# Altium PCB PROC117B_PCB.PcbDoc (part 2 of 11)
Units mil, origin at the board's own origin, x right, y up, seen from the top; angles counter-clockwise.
Board outline 2480.32 x 3185.25 mil, 8 copper layers (Top Layer, L2_GND1, L3_SIG1, L4_PWR1, L5_PWR2, L6_SIG2, L7_GND2, Bottom Layer), stack 57.4 mil thick; 456 components, 292 nets, 7831 pads, 2905 vias.

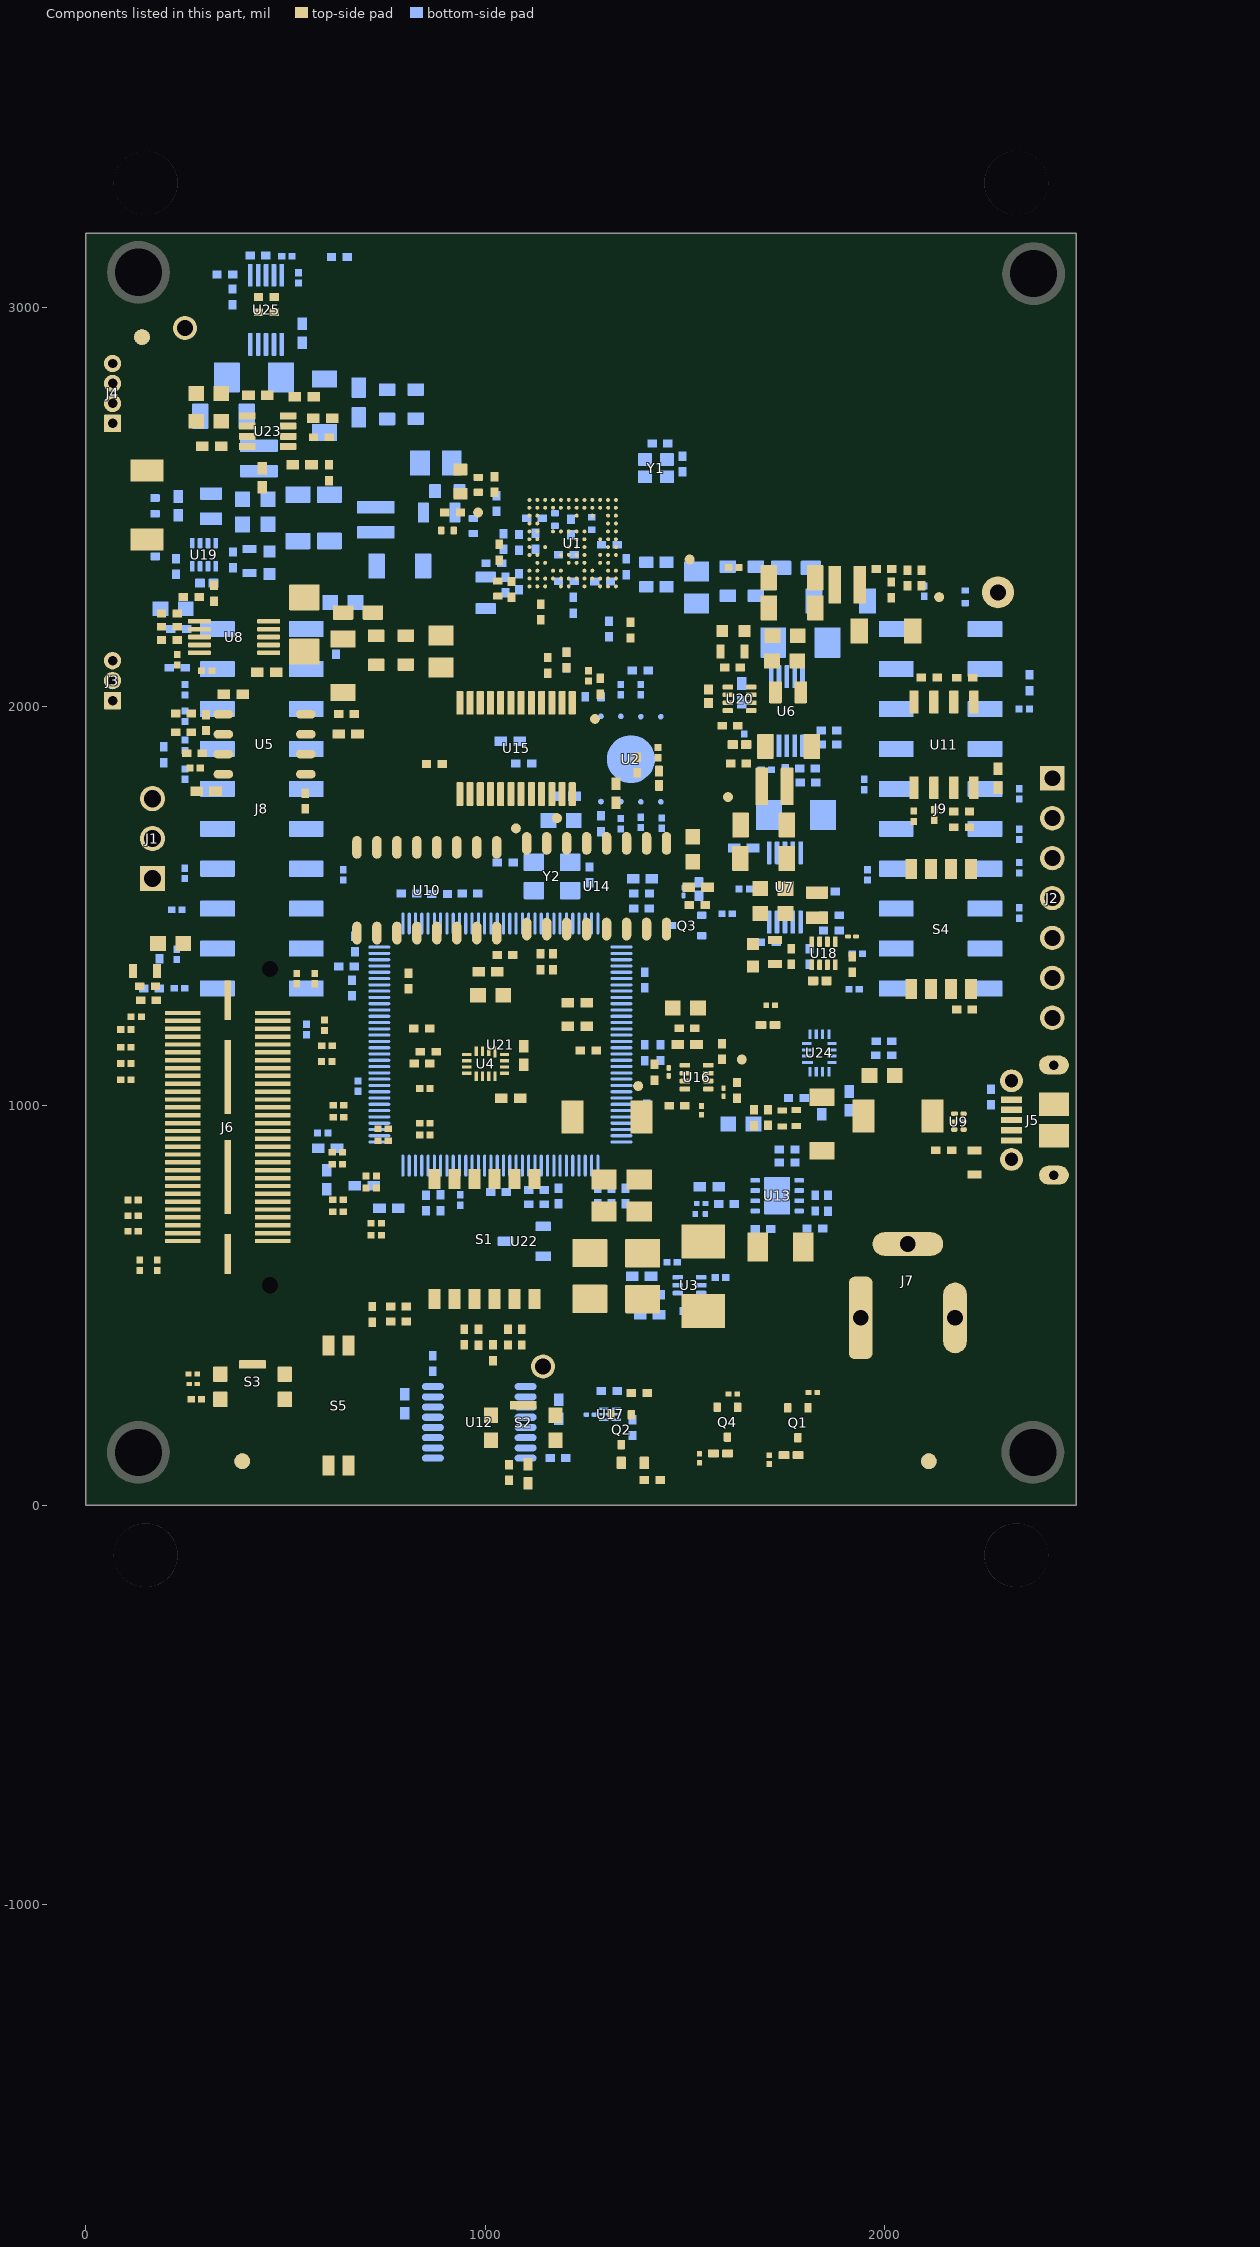
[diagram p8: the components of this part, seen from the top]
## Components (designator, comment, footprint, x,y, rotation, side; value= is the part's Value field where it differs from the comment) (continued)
R137 "CRCW02010000Z0ED" 0201 532.63,3073.14 r270 bottom
R138 "CRCW040210K0FKED" 0402L 1369.02,194.08 r270 bottom
R139 "CRCW02010000Z0ED" 0201 503.6,3127.45 r0 bottom
R140 "CRCW02010000Z0ED" 0201_Silk 2350.08,1993.71 r0 bottom
R141 "RC0201JR-07510RL" 0201L 1711.5,114.16 r90 top
R142 "CRCW040210K0FKED" 0402L 431.44,3128.96 r0 bottom
R143 "CRCW02010000Z0ED" 0201_Silk 1949.41,1804.6 r270 bottom
R144 "CRCW02010000Z0ED" 0201_Silk 2337.72,1781.04 r270 bottom
R145 "CRCW02010000Z0ED" 0201_Silk 2337.72,1679.83 r270 bottom
R146 "CRCW02010000Z0ED" 0201_Silk 247.61,1581.92 r90 bottom
R147 "CRCW02010000Z0ED" 0201_Silk 1957.66,1578.25 r90 bottom
R148 "CRCW040210K0FKED" 0402L 452.2,2987.41 r180 top
R149 "CRCW02010000Z0ED" 0201_Silk 228.01,1491.41 r0 bottom
R150 "CRCW040210K0FKED" 0402L 367.15,3025.77 r90 bottom
R151 "CRCW04020000Z0ED" 0402 1411.3,526.51 r0 bottom
R152 "CRCW040210K0FKED" 0402L 1998.2,1126.65 r0 bottom
R153 "CRCW02010000Z0ED" 0201_Silk 2337.72,1596.25 r90 bottom
R154 "CRCW02010000Z0ED" 0201_Silk 227.56,1379.15 r90 bottom
R155 "CRCW02010000Z0ED" 0201_Silk 1932.27,1380.28 r0 bottom
R156 "ERJ-2GE0R00X" 0402L 841.93,1105.72 r0 top
R157 "CRCW040210K0FKED" 0402L 2193.38,1737.31 r0 top
R158 "CRCW040210K0FKED" 0402L 2193.38,1697.45 r180 top
R159 "CRCW02010000Z0ED" 0201 2124.33,1728.34 r270 top
R160 "CRCW02010000Z0ED" 0201 2073.05,1724.99 r270 top
R161 "CRCW040210K0FKED" 0402L 2200.92,2071.84 r0 top
R162 "CRCW040210K0FKED" 0402L 2112.15,2072.49 r0 top
R163 "CRCW02010000Z0ED" 0201_Silk 234.77,1294.83 r0 bottom
R164 "CRCW02010000Z0ED" 0201_Silk 1924,1291.98 r0 bottom
R165 "CRCW040210K0FKED" 0402L 1059.52,81.96 r270 top
R169 "ERJ-2GEJ101X" 0402L 1391.89,1531.41 r0 bottom
R170 "ERJ-2GE0R00X" 0402 1394.09,1568.73 r0 bottom
R171 "RC0201JR-07510RL" 0201L 1821,281.86 r180 top
R172 "ERJ-2GEJ511X" 0402L 1418.73,62.98 r0 top
R173 "RC0201JR-070RL" "FP-RC0201JR-070RL_0201 (0603 Metric)-IPC_C" 1496.97,1536.63 r90 bottom
R174 "RC0201JR-07510RL" 0201L 1714.78,1251.78 r0 top
R175 "CRCW0402100KFKEDC" FP-CRCW0402100KFKEDC_0402-IPC_B 1637.01,1904.61 r0 top
R176 "RC0201JR-070RL" "FP-RC0201JR-070RL_0201 (0603 Metric)-IPC_C" 1918.75,1423.57 r180 top
R177 "CRCW0402100KFKEDC" FP-CRCW0402100KFKEDC_0402-IPC_B 1535.32,1542.64 r270 bottom
R178 "CRCW040218K0FKED" 0402L 225.59,2350.58 r270 bottom
R179 "ERJ-2GEJ511X" 0402L 1385.79,280.58 r180 top
R180 "CRCW040218K0FKED" 0402L 1613.02,1951.77 r180 top
R181 "ERJ-2GE0R00X" 0402 696.96,800.08 r180 bottom
R182 "HCJ0603ZT0R00" FP-HCJ0603ZT0R00_0603-MFG 1778.48,2346.91 r180 bottom
R183 "HCJ0603ZT0R00" FP-HCJ0603ZT0R00_0603-MFG 681.62,2235.22 r0 top
R188 "ERJ-2GE0R00X" 0402 605.47,893.62 r0 bottom
R190 "CRCW02010000Z0ED" 0201_Silk 937.61,763.99 r90 bottom
R191 "CRCW04021K00FKED" 0402L 674.18,1405.38 r90 bottom
R192 "WSL1206R0400FEB" FP-WSL1206R0400FEB_1206-MFG 1789.48,2159.94 r180 bottom
R193 "WSL1206R0400FEB" FP-WSL1206R0400FEB_1206-MFG 547.27,2205.5 r270 top
R194 "CRCW04021K00FKED" 0402L 652.72,1348.51 r180 bottom
R195 "CRCW04021K00FKED" 0402L 841.25,1193.16 r180 top
R196 "CRCW04021K00FKED" 0402L 808.39,1312.74 r270 top
R197 "ERJ-2GE0R00X" 0402 1230.59,1257.95 r0 top
R198 "RC0201JR-070RL" "FP-RC0201JR-070RL_0201 (0603 Metric)-MFG" 1538.99,728.87 r180 bottom
R199 "ERJ-2GE0R00X" 0402 1230.59,1198.69 r0 top
R200 "WSL1206R0400FEB" FP-WSL1206R0400FEB_1206-MFG 1778.3,1728.34 r0 bottom
R201 "CRCW0201100KFKED" 0201L 1540.68,755.51 r0 bottom
R202 "CRCW040249R9FKED" 0402L 962.23,1531.94 r180 bottom
R203 "CRCW040210K0FKED" 0402L 857.45,1135.38 r0 top
R204 "CRCW04027K87FKED" 0402L 783.2,497.74 r0 top
R205 "CRCW040282K5FKED" 0402L 717.37,477.73 r90 top
R206 "CRCW040210K0FKED" 0402L 1056.91,420.72 r270 top
R207 "CRCW04027K87FKED" 0402L 983.78,420.38 r90 top
R208 "CRCW040282K5FKED" 0402L 1019.54,381.59 r90 top
R213 "RC0201JR-07220RL" 0201 277,264.9 r180 top
R214 "RC0201JR-070RL" "FP-RC0201JR-070RL_0201 (0603 Metric)-IPC_C" 269.29,303.27 r180 top
R215 "CRCW0201100KFKED" 0201L 268.39,327.93 r180 top
R219 "CRCW02010000Z0ED" 0201_Silk 632.84,1001.22 r0 top
R220 "CRCW02010000Z0ED" 0201_Silk 632.84,971.22 r0 top
R221 "CRCW02010000Z0ED" 0201_Silk 744.45,942.84 r0 top
R222 "CRCW02010000Z0ED" 0201_Silk 744.45,912.84 r0 top
R223 "CRCW02010000Z0ED" 0201_Silk 630.17,884 r0 top
R224 "CRCW02010000Z0ED" 0201_Silk 630.17,854 r0 top
R225 "CRCW02010000Z0ED" 0201_Silk 714.97,824.08 r0 top
R226 "CRCW02010000Z0ED" 0201_Silk 714.97,794.08 r0 top
R227 "CRCW02010000Z0ED" 0201_Silk 631.62,765.03 r0 top
R228 "CRCW02010000Z0ED" 0201_Silk 631.62,735.03 r0 top
R229 "CRCW02010000Z0ED" 0201_Silk 727.5,705.97 r0 top
R230 "CRCW02010000Z0ED" 0201_Silk 727.5,675.97 r0 top
R231 "CRCW040210K0FKED" 0402L 886.06,1530.6 r180 bottom
R232 "CRCW0402100KFKEDC" FP-CRCW0402100KFKEDC_0402-IPC_B 1838.13,1313.11 r0 top
R233 "CRCW04021K00FKED" 0402L 1183.89,774.29 r90 bottom
R234 "CRCW04024K87FKED" 0402L 666.49,1294.83 r90 bottom
R236 "CRCW0402330KFKED" 0402L 1351.75,773.94 r270 bottom
R238 "CRCW0402100KFKEDC" FP-CRCW0402100KFKEDC_0402-IPC_B 302.89,2308.62 r180 bottom
R239 "CRCW0402330KFKED" 0402L 1282.09,773.94 r90 bottom
R241 "ERJ-2GE0R00X" 0402 1560.96,797.47 r0 bottom
R244 "CRCW0402100KFKEDC" FP-CRCW0402100KFKEDC_0402-IPC_B 1559.69,2025.63 r270 top
S1 "218-6LPST" SW_218-6LPST 998.28,666.28 r90 top
S2 "KMR243GLFG" SW_KMR243GLFG 1095.36,193.75 r0 top
S3 "KMR243GLFG" SW_KMR243GLFG 417.49,296.36 r0 top
S4 "218-4LPST" SW_218-4LPST 2142.14,1442.74 r270 top
S5 "218-2LPST" SW_218-2LP 632.84,249.25 r90 top
TP1 "TESTPOINT" TP_VIA_060RND040 1145.25,347.45 r270 top
TP2 "TESTPOINT" TP_25MIL-SMT 1274.9,1968.89 r90 top
TP3 "TESTPOINT" TP_25MIL-SMT 1077.13,1694.73 r90 top
TP4 "TESTPOINT" TP_25MIL-SMT 1180.04,1720.28 r90 top
TP5 "TESTPOINT" TP_25MIL-SMT 1512.19,2368.21 r90 top
TP6 "TESTPOINT" TP_25MIL-SMT 982.47,2485.72 r90 top
TP7 "TESTPOINT" TP_25MIL-SMT 2137.05,2273.88 r90 top
TP8 "TESTPOINT" TP_25MIL-SMT 1642.77,1116.02 r0 top
TP9 "TESTPOINT" TP_25MIL-SMT 1608.13,1773.05 r0 top
TP10 "5001" Keystone5001 2284.36,2285.93 r90 top
TP11 "TESTPOINT" TP_VIA_060RND040 248.36,2947.57 r180 top
TP12 "TESTPOINT" TP_25MIL-SMT 1383.24,1049.37 r180 top
U1 "IWRL6432QGAMF" AMF0102A-MFG 1219.26,2408.99 r270 top locked
U2 "MX25V1635FZNQ03" FP-MX25V1635FZNQ03_WSON8-MFG 1365.12,1868.19 r270 bottom
U3 "TMP112AQDRLRQ1" DRL0006A 1511.78,550.63 r180 bottom
U4 "TS3A5018RSVR" RSV0016A 1001.27,1105.02 r270 top
U5 "TCAN1042HGVDQ1" D0008A_L 447.73,1905.45 r0 top
U6 "INA228AIDGST" DGS0010A-MFG 1755.6,1988.23 r90 bottom
U7 "INA228AIDGST" DGS0010A-MFG 1750.8,1546.8 r90 bottom
U8 "INA228AIDGST" DGS0010A-MFG 371.18,2173.77 r0 top
U9 "TPD4E004DRYR" DRY0006A 2186.45,960.29 r0 top
U10 "SN65LVDS31MDREP" D0016A_N 854.03,1539.9 r270 top locked
U11 "CAT24C08WI-GT3" SOIC-8 2148.96,1903.96 r270 top
U12 "TS3A44159PWR" PW0016A_N 985.32,207.25 r0 bottom
U13 "TPS79601DRBR" DRB0008B 1731.38,774.87 r180 bottom
U14 "SN65LVDS31MDREP" D0016A_N 1279.22,1549.9 r270 top locked
U15 "TS3A27518EPWR" PW0024A-MFG 1077.43,1894.93 r270 top
U16 "TPS2116DRLR" DRL0008A-MFG 1529.63,1071.74 r0 top
U17 "SN74LVC1G11DSFR" DSF0006A 1312.89,227.49 r180 bottom
U18 "TPS6285021HQDRLRQ1" DRL0008A-MFG 1847.48,1382.07 r90 top
U19 "TPS628502QDRLRQ1" DRL0008A-MFG 296,2380.17 r90 bottom
U20 "TPS6285020MQDRLRQ1" DRL0008A-MFG 1637.3,2019.27 r0 top
U21 "TM4C1294NCPDTT3" PDT0128A 1038.21,1153.31 r90 bottom locked
U22 "LM4040C25QDBZR" DBZ0003A_N 1098.48,660.56 r180 bottom
U23 "TLIN1039DDFRQ1" DDF0008A-MFG 455.49,2689.41 r180 top
U24 "TS3A5018RSVR" RSV0016A 1837.22,1132.23 r0 bottom
U25 "INA228AIDGST" DGS0010A-MFG 451.49,2993.23 r270 bottom
Y1 "FW4000044Q" FP-FW4000044Q_4-SMD-2.0x1.6mm-MFG 1427.89,2596.78 r180 bottom
Y2 "ECS-160-8-33Q-RES-TR" FP-ECS-160-8-33Q-RES-TR_SMT4_3MM2_2MM5-MFG 1167.48,1574.31 r0 bottom
ZZ1 "This Assembly Note is for PCB labels only" AssemblyNoteLabel -715.46,4127.58 r0 top
ZZ2 "These assemblies are ESD sensitive, ESD precautions shall be observed." AssemblyNote -713.05,4049.6 r0 top
ZZ3 "These assemblies must be clean and free from flux and all contaminants. Use of no clean flux is not acceptable." AssemblyNote -713.05,3962.79 r0 top
ZZ4 "These assemblies must comply with workmanship standards IPC-A-610 Class 2, unless otherwise specified." AssemblyNote -692.48,3894.06 r0 top
ZZ5 "INDICATION FOR COMPONENTS D* ARE GIVEN AT THEIR CATHODE SIDE." AssemblyNote -691.09,3806.47 r0 top

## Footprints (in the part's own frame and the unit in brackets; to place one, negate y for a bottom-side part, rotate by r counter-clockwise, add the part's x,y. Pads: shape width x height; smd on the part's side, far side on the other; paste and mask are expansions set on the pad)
0201 [mm] "Data from Kemet datasheet CC101_COM dated 7/28/11"
  rect 0.46x0.42 smd mask+0: 1(-0.33,0) 2(0.33,0)
0201_Silk [mm] "Data from Kemet datasheet CC101_COM dated 7/28/11"
  rect 0.46x0.42 smd mask+0: 1(-0.33,0) 2(0.33,0)
  silkscreen extent -0.75,-0.4 0.75,0.4
0201L [mm] "Data from Kemet datasheet CC101_COM dated 7/28/11"
  rect 0.36x0.32 smd mask+0: 1(-0.28,0) 2(0.28,0)
0402 [mm] "0402 from SM-752 data"
  rect 0.8x0.6 smd: 1(-0.6,0) 2(0.6,0)
  silkscreen extent -1.22,-0.52 1.22,0.52
0402_065L [mm] "0402"
  rect 0.6x0.5 smd: 1(-0.5,0) 2(0.5,0)
0402_070 [mil] "SMD, 2-Leads, Body 1.2x0.7mm, Height 0.7mm"
  rect 15x24 smd: 1(-20,0) 2(20,0)
0402L [mm] "0402 from SM-752 data"
  rect 0.6x0.5 smd: 1(-0.5,0) 2(0.5,0)
0603 [mm] "0603 from SM-752 data"
  rect 1x0.95 smd: 1(-0.8,0) 2(0.8,0)
  silkscreen extent -1.52,-0.69 1.52,0.69
0603_HV [mil] "Ernesto recommended land pattern.  26 mil between pads."
  rect 30x30 smd: 1(-28,0) 2(28,0)
  silkscreen extent -52,-24 52,24
0603S [mil]
  rect 20x35 smd: 1(-30,0) 2(30,0)
0805_HV [mil] "0805 with 30mil clearance between pads"
  rect 50x63 smd: 1(-40,0) 2(40,0)
  silkscreen extent -74,-40 74,40
1206 [mm] "1206 from SM-752 data"
  rect 1.3x1.85 smd: 1(-1.45,0) 2(1.45,0)
  silkscreen extent -2.4,-1.21 2.4,1.21
1206_180 [mm] "1206_180"
  rect 1.1x1.6 smd: 1(-1.7,0) 2(1.7,0)
  silkscreen extent -0.9,-1 0.9,1
3528-21 [mm] "Medium Density IPC, based on Kemet datasheet 2016-10-20"
  rrect6% 1.8x2.23 smd: 1(-1.46,0) 2(1.46,0)
  silkscreen extent -2.29,-1.5 0.76,1.5
AMF0102A-MFG [mm]
  round 0.25 smd paste+0 mask+0: A1(-2.75,2.75) A2(-2.25,2.75) A3(-1.75,2.75) A4(-1.25,2.75) A5(-0.75,2.75) A6(-0.25,2.75) A7(0.25,2.75) A8(0.75,2.75) A10(1.75,2.75) A11(2.25,2.75) A12(2.75,2.75) B1(-2.75,2.25) B2(-2.25,2.25) B3(-1.75,2.25) B4(-1.25,2.25) B5(-0.75,2.25) B6(-0.25,2.25) B7(0.25,2.25) B8(0.75,2.25) B9(1.25,2.25) B10(1.75,2.25) B11(2.25,2.25) B12(2.75,2.25) C1(-2.75,1.75) C2(-2.25,1.75) C6(-0.25,1.75) C8(0.75,1.75) C9(1.25,1.75) C11(2.25,1.75) C12(2.75,1.75) D1(-2.75,1.25) D2(-2.25,1.25) D3(-1.75,1.25) D10(1.75,1.25) D11(2.25,1.25) E1(-2.75,0.75) E2(-2.25,0.75) E5(-0.75,0.75) E6(-0.25,0.75) E7(0.25,0.75) E8(0.75,0.75) E9(1.25,0.75) E10(1.75,0.75) E11(2.25,0.75) E12(2.75,0.75) F1(-2.75,0.25) F2(-2.25,0.25) F3(-1.75,0.25) F5(-0.75,0.25) F6(-0.25,0.25) F7(0.25,0.25) F8(0.75,0.25) F9(1.25,0.25) F11(2.25,0.25) G1(-2.75,-0.25) G2(-2.25,-0.25) G5(-0.75,-0.25) G7(0.25,-0.25) G8(0.75,-0.25) G9(1.25,-0.25) G11(2.25,-0.25) G12(2.75,-0.25) H1(-2.75,-0.75) H2(-2.25,-0.75) H5(-0.75,-0.75) H8(0.75,-0.75) H10(1.75,-0.75) H11(2.25,-0.75) H12(2.75,-0.75) J1(-2.75,-1.25) J2(-2.25,-1.25) J5(-0.75,-1.25) J10(1.75,-1.25) J11(2.25,-1.25) K1(-2.75,-1.75) K2(-2.25,-1.75) K7(0.25,-1.75) K9(1.25,-1.75) K11(2.25,-1.75) K12(2.75,-1.75) L1(-2.75,-2.25) L2(-2.25,-2.25) L3(-1.75,-2.25) L4(-1.25,-2.25) L5(-0.75,-2.25) L6(-0.25,-2.25) L8(0.75,-2.25) L9(1.25,-2.25) L10(1.75,-2.25) L11(2.25,-2.25) L12(2.75,-2.25) M1(-2.75,-2.75) M2(-2.25,-2.75) M3(-1.75,-2.75) M4(-1.25,-2.75) M5(-0.75,-2.75) M6(-0.25,-2.75) M7(0.25,-2.75) M8(0.75,-2.75) M10(1.75,-2.75) M11(2.25,-2.75) M12(2.75,-2.75)
  silkscreen extent -3.87,-3.27 3.27,3.27
APHHS1005_Green [mm] "SMD, 2-Leads, Body 1x0.5mm"
  rrect20% 0.7x0.5 smd: 1(-0.45,0) 2(0.45,0)
  silkscreen extent -0.8,-0.65 1.2,0.65
APHHS1005_Red [mm] "SMD, 2-Leads, Body 1x0.5mm"
  rrect20% 0.7x0.5 smd: 1(-0.45,0) 2(0.45,0)
  silkscreen extent -0.8,-0.65 1.2,0.65
AssemblyNote [mil] "Assembly Note"
AssemblyNoteLabel [mil] "Assembly Note for PCB Labels"
CE_Mark_5mm [mil] "Minimum text height for CE Mark"
CONN_105017-0001 [mm] "Molex Micro USB-B"
  rect 0.4x1.35 smd: 1(-1.3,1.35) 2(-0.65,1.35) 3(0,1.35) 4(0.65,1.35) 5(1.3,1.35)
  oval 1.2x1.9 hole 0.6 slot 1.3 at 90 deg: 6(-3.5,-1.35) 9(3.5,-1.35)
  rect 1.5x1.9 smd: 7(-1,-1.35) 8(1,-1.35)
  round 1.45 hole 0.85: 10(2.5,1.35) 11(-2.5,1.35)
  Top Layer region: 3.499,-0.399 2.299,-0.399 2.299,-2.299 3.499,-2.299
  Top Layer region: -3.5,-2.299 -2.3,-2.299 -2.3,-0.399 -3.5,-0.399
  silkscreen extent -4.1,-0.2 4.1,1.4
CUI_PJ-002AH [mm] "DC POWER JACK, R/A, TH"
  rrect50% 1.5x5.25 hole 1 square: 1(-3,0)
  oval 1.5x4.5 hole 1 square: 2(3,0)
  oval 4.5x1.5 hole 1 square: 3(0,4.7)
  silkscreen extent -4.1,-4.5 10.7,4.5
D0008A_L [mm] "SOIC, 8-Leads, Body 4.9x3.9mm, Pitch 1.27mm, IPC High Density"
  oval 1.25x0.55 smd: 1(-2.625,1.905) 2(-2.625,0.635) 3(-2.625,-0.635) 4(-2.625,-1.905) 5(2.625,-1.905) 6(2.625,-0.635) 7(2.625,0.635) 8(2.625,1.905)
  silkscreen extent -3.1,-2.5 0.9,2.5
D0016A_N [mm] "SOIC, 16-Leads, Body 9.9x3.9mm, Pitch 1.27mm, IPC Medium Density"
  oval 1.45x0.6 smd: 1(-2.725,4.445) 2(-2.725,3.175) 3(-2.725,1.905) 4(-2.725,0.635) 5(-2.725,-0.635) 6(-2.725,-1.905) 7(-2.725,-3.175) 8(-2.725,-4.445) 9(2.725,-4.445) 10(2.725,-3.175) 11(2.725,-1.905) 12(2.725,-0.635) 13(2.725,0.635) 14(2.725,1.905) 15(2.725,3.175) 16(2.725,4.445)
  silkscreen extent -3.3,-5 0.9,5
DBZ0003A_N [mm] "SOT23, 3-Leads, Body 2.9x1.3mm, Pitch 0.95mm, Lead Span 2.4mm, IPC Medium Density"
  rrect17% 1x0.6 smd: 1(-1.2,0.95) 2(-1.2,-0.95) 3(1.2,0)
  silkscreen extent 0.2,-1.5 0.7,1.5
DDF0008A-MFG [mm]
  rrect22% 1.05x0.45 smd paste+0 mask+0: 1(-1.3,0.975) 2(-1.3,0.325) 3(-1.3,-0.325) 4(-1.3,-0.975) 5(1.3,-0.975) 6(1.3,-0.325) 7(1.3,0.325) 8(1.3,0.975)
  silkscreen extent -2.5,-1.48 0.4,1.48
DGS0010A-MFG [mm]
  rrect33% 1.45x0.3 smd paste+0 mask+0: 1(-2.2,1) 2(-2.2,0.5) 3(-2.2,0) 4(-2.2,-0.5) 5(-2.2,-1) 6(2.2,-1) 7(2.2,-0.5) 8(2.2,0) 9(2.2,0.5) 10(2.2,1)
  silkscreen extent -3.6,-1.55 1.05,1.55
DRB0008B [mm] "SON, 8-Leads, Body 3x3mm, Pitch 0.65mm, Thermal Pad 2.4x1.65mm, TI Recommended"
  rrect33% 0.6x0.3 smd: 1(-1.4,0.975) 2(-1.4,0.325) 3(-1.4,-0.325) 4(-1.4,-0.975) 5(1.4,-0.975) 6(1.4,-0.325) 7(1.4,0.325) 8(1.4,0.975)
  rrect9% 1.47x1.06 on Bottom Paste: 9(0,-0.63) 9(0,0.63)
  rrect6% 1.65x2.4 smd paste-1.2: 9(0,0)
  silkscreen extent -1.73,-1.73 1.73,1.73
DRL0006A [mm] "SOTFL, 6-Flat Leads, Body 1.2x1.6x0.6mm, Pitch 0.5mm, TI recommended"
  rrect33% 0.67x0.3 smd: 1(-0.74,0.5) 2(-0.74,0) 3(-0.74,-0.5) 4(0.74,-0.5) 5(0.74,0) 6(0.74,0.5)
  silkscreen extent -0.9,-0.95 0.5,0.95
DRL0008A-MFG [mm]
  rrect33% 0.67x0.3 smd paste+0 mask+0: 1(-0.74,0.75) 2(-0.74,0.25) 3(-0.74,-0.25) 4(-0.74,-0.75) 5(0.74,-0.75) 6(0.74,-0.25) 7(0.74,0.25) 8(0.74,0.75)
  silkscreen extent -1.13,-1.28 0.65,1.35
DRY0006A [mm] "USON-6"
  rrect67% 0.45x0.3 smd paste-0.05 mask+0: 1(-0.275,0.5)
  rrect67% 0.4x0.3 smd paste-0.05 mask+0: 2(-0.3,0) 3(-0.3,-0.5) 4(0.3,-0.5) 5(0.3,0) 6(0.3,0.5)
DSF0006A [mm] "TI recommended land pattern"
  rrect59% 0.6x0.17 smd mask+0: 1(-0.4,0.35) 2(-0.4,0) 3(-0.4,-0.35) 4(0.4,-0.35) 5(0.4,0) 6(0.4,0.35)
  silkscreen extent -0.6,-0.63 0.6,0.63
FCC_disclaimer [mil]
Fiducial10-20 [mm]
  round 1 smd mask+0: 1(0,0)
  Top Layer keep-out circle w1.178: c0,0 r0.5
FP-AC0402FR-0747K5L_0402-MFG [mm]
  rrect20% 0.5x0.6 smd paste+0 mask+0: 1(-0.5,0) 2(0.5,0)
  silkscreen extent -0.5,-0.67 0.5,0.67
FP-CGA4J1X7T0J226M125AC_0805-MFG [mm]
  rrect13% 0.8x1.05 smd paste+0 mask+0: 1(-0.925,0) 2(0.925,0)
  silkscreen extent -0.15,-0.78 0.15,0.77
FP-CRCW0402100KFKEDC_0402-IPC_B [mil]
  rrect17% 25.97x22.54 smd paste+0 mask+0: 1(-16.78,0) 2(16.78,0)
  silkscreen extent -30,-27 30,27
"FP-DFE201210U-R47M=P2_0805 (2012)-MFG" [mm]
  rrect13% 0.8x1.4 smd paste+0 mask+0: 1(-0.8,0) 2(0.8,0)
  silkscreen extent -1.2,-1.07 1.2,1.08
FP-ECS-160-8-33Q-RES-TR_SMT4_3MM2_2MM5-MFG [mm]
  rrect9% 1.3x1.1 smd paste+0 mask+0: 1(-1.15,-0.9) 2(1.15,-0.9) 3(1.15,0.9) 4(-1.15,0.9)
  silkscreen extent -1.52,-1.96 0.13,1.3
FP-FW4000044Q_4-SMD-2.0x1.6mm-MFG [mm]
  rrect13% 0.9x0.8 smd paste+0 mask+0: 1(-0.7,-0.55) 2(0.7,-0.55) 3(0.7,0.55) 4(-0.7,0.55)
  silkscreen extent -1.4,-1.1 1.01,1.13
FP-GCJ21BR71C475KA01L_0805-MFG [mm]
  rrect14% 0.7x1.3 smd paste+0 mask+0: 1(-1,0) 2(1,0)
  silkscreen extent -0.28,-0.73 0.28,0.73
FP-GCM188D70J106ME36D_0603-MFG [mm]
  rrect13% 0.75x0.9 smd paste+0 mask+0: 1(-0.775,0) 2(0.775,0)
FP-GRM31CR70J226ME19K_1206-MFG [mm]
  rrect10% 1.05x1.6 smd paste+0 mask+0: 1(-1.475,0) 2(1.475,0)
  silkscreen extent -0.58,-0.9 0.58,0.9
"FP-GRM033R6YA104KE14D_0201 (0603 Metric)-IPC_C" [mil]
  rrect38% 13.94x10.34 smd paste+0 mask+0: 1(-10.01,0) 2(10.01,0)
FP-GRT155C71A225KE13D_0402-MFG [mm]
  rrect22% 0.45x0.6 smd paste+0 mask+0: 1(-0.475,0) 2(0.475,0)
  silkscreen extent -0.5,-0.45 0.5,0.44
FP-GRT155R70J105KE01D_0402-MFG [mm]
  rrect25% 0.4x0.5 smd paste+0 mask+0: 1(-0.4,0) 2(0.4,0)
  silkscreen extent -0.53,-0.63 0.52,0.63
FP-HCJ0603ZT0R00_0603-MFG [mm]
  rrect11% 1.3x0.92 smd paste+0 mask+0: 1(-0.95,0) 2(0.95,0)
  silkscreen extent -0.9,-0.83 0.9,0.83
"FP-LQM2MPZR10MJHL_0806 (2016)-MFG" [mm]
  rrect13% 0.8x2.4 smd paste-1000 mask+0: 1(-0.8,0) 2(0.8,0)
  silkscreen extent -1.1,-1.5 1.1,1.5
FP-M50-3930342_HDR3-MFG [mm]
  rrect9% 1.1x1.1 hole 0.6 paste-1000 mask+0: 1(-1.27,1)
  round 1.1 hole 0.6 paste-1000 mask+0: 2(0,1) 3(1.27,1)
  silkscreen extent -2.16,-0.6 2.15,2.18
FP-M50-3930442_HDR4-Recommended_Land_Pattern [mm]
  rrect9% 1.1x1.1 hole 0.6 paste-1000 mask+0: 1(-1.905,1)
  round 1.1 hole 0.6 paste-1000 mask+0: 2(-0.635,1) 3(0.635,1) 4(1.905,1)
FP-MX25V1635FZNQ03_WSON8-MFG [mm]
  round 0.36 smd paste+0 mask+0: 1(-2.72,1.905) 2(-2.72,0.635) 3(-2.7,-0.635) 4(-2.7,-1.905) 5(2.72,-1.905) 6(2.72,-0.635) 7(2.7,0.635) 8(2.7,1.905)
  round 3.06 smd paste+0 mask+0: 9(0,0)
  silkscreen extent -3.05,-2.55 3.05,3.1
"FP-RC0201JR-070RL_0201 (0603 Metric)-IPC_C" [mil]
  rrect38% 13.94x10.34 smd paste+0 mask+0: 1(-10.01,0) 2(10.01,0)
"FP-RC0201JR-070RL_0201 (0603 Metric)-MFG" [mm]
  rrect29% 0.35x0.4 smd paste+0 mask+0: 1(-0.325,0) 2(0.325,0)
FP-RMCF0402FT68K0_0402-MFG [mm]
  rrect20% 0.5x0.6 smd paste+0 mask+0: 1(-0.5,0) 2(0.5,0)
  silkscreen extent -0.55,-0.7 0.55,0.7
FP-WSL1206R0200FEB_1206-MFG [mm]
  rrect6% 1.65x1.93 smd paste+0 mask+0: 1(-1.725,0) 2(1.725,0)
  silkscreen extent -0.53,-0.93 0.53,0.93
FP-WSL1206R0400FEB_1206-MFG [mm]
  rrect6% 1.65x1.93 smd paste+0 mask+0: 1(-1.725,0) 2(1.725,0)
  silkscreen extent -0.53,-0.93 0.53,0.93
IEC_HotSurface_Small [mil]
  silkscreen extent -107,-93 107,92
Keystone5001 [mil] "For Keystone 500x miniature loop terminals"
  round 80 hole 40: 1(0,0)
  silkscreen extent -52,-52 52,52
Label_650x200 [mil] "Thermal Transfer Label"
  round 1 on Mech14: 0(0,0)
  silkscreen extent -325,-100 325,100
PDT0128A [mm] "Thin QFP, 128-Leads, Body 14x14mm, Pitch 0.4mm"
  oval 1.4x0.2 smd: 1(-7.7,6.2) 2(-7.7,5.8) 3(-7.7,5.4) 4(-7.7,5) 5(-7.7,4.6) 6(-7.7,4.2) 7(-7.7,3.8) 8(-7.7,3.4) 9(-7.7,3) 10(-7.7,2.6) 11(-7.7,2.2) 12(-7.7,1.8) 13(-7.7,1.4) 14(-7.7,1) 15(-7.7,0.6) 16(-7.7,0.2) 17(-7.7,-0.2) 18(-7.7,-0.6) 19(-7.7,-1) 20(-7.7,-1.4) 21(-7.7,-1.8) 22(-7.7,-2.2) 23(-7.7,-2.6) 24(-7.7,-3) 25(-7.7,-3.4) 26(-7.7,-3.8) 27(-7.7,-4.2) 28(-7.7,-4.6) 29(-7.7,-5) 30(-7.7,-5.4) 31(-7.7,-5.8) 32(-7.7,-6.2) 65(7.7,-6.2) 66(7.7,-5.8) 67(7.7,-5.4) 68(7.7,-5) 69(7.7,-4.6) 70(7.7,-4.2) 71(7.7,-3.8) 72(7.7,-3.4) 73(7.7,-3) 74(7.7,-2.6) 75(7.7,-2.2) 76(7.7,-1.8) 77(7.7,-1.4) 78(7.7,-1) 79(7.7,-0.6) 80(7.7,-0.2) 81(7.7,0.2) 82(7.7,0.6) 83(7.7,1) 84(7.7,1.4) 85(7.7,1.8) 86(7.7,2.2) 87(7.7,2.6) 88(7.7,3) 89(7.7,3.4) 90(7.7,3.8) 91(7.7,4.2) 92(7.7,4.6) 93(7.7,5) 94(7.7,5.4) 95(7.7,5.8) 96(7.7,6.2)
  oval 0.2x1.4 smd: 33(-6.2,-7.7) 34(-5.8,-7.7) 35(-5.4,-7.7) 36(-5,-7.7) 37(-4.6,-7.7) 38(-4.2,-7.7) 39(-3.8,-7.7) 40(-3.4,-7.7) 41(-3,-7.7) 42(-2.6,-7.7) 43(-2.2,-7.7) 44(-1.8,-7.7) 45(-1.4,-7.7) 46(-1,-7.7) 47(-0.6,-7.7) 48(-0.2,-7.7) 49(0.2,-7.7) 50(0.6,-7.7) 51(1,-7.7) 52(1.4,-7.7) 53(1.8,-7.7) 54(2.2,-7.7) 55(2.6,-7.7) 56(3,-7.7) 57(3.4,-7.7) 58(3.8,-7.7) 59(4.2,-7.7) 60(4.6,-7.7) 61(5,-7.7) 62(5.4,-7.7) 63(5.8,-7.7) 64(6.2,-7.7) 97(6.2,7.7) 98(5.8,7.7) 99(5.4,7.7) 100(5,7.7) 101(4.6,7.7) 102(4.2,7.7) 103(3.8,7.7) 104(3.4,7.7) 105(3,7.7) 106(2.6,7.7) 107(2.2,7.7) 108(1.8,7.7) 109(1.4,7.7) 110(1,7.7) 111(0.6,7.7) 112(0.2,7.7) 113(-0.2,7.7) 114(-0.6,7.7) 115(-1,7.7) 116(-1.4,7.7) 117(-1.8,7.7) 118(-2.2,7.7) 119(-2.6,7.7) 120(-3,7.7) 121(-3.4,7.7) 122(-3.8,7.7) 123(-4.2,7.7) 124(-4.6,7.7) 125(-5,7.7) 126(-5.4,7.7) 127(-5.8,7.7) 128(-6.2,7.7)
  silkscreen extent -7.7,-6.3 6.3,7
PW0016A_N [mm] "TSOP, 16-Leads, Body 5x4.4mm, Pitch 0.65mm, IPC Medium Density"
  oval 1.4x0.45 smd: 1(-2.95,2.275) 2(-2.95,1.625) 3(-2.95,0.975) 4(-2.95,0.325) 5(-2.95,-0.325) 6(-2.95,-0.975) 7(-2.95,-1.625) 8(-2.95,-2.275) 9(2.95,-2.275) 10(2.95,-1.625) 11(2.95,-0.975) 12(2.95,-0.325) 13(2.95,0.325) 14(2.95,0.975) 15(2.95,1.625) 16(2.95,2.275)
  silkscreen extent -3.5,-2.55 1.85,2.75
PW0024A-MFG [mm]
  rrect22% 1.5x0.45 smd paste+0 mask+0: 1(-2.9,3.575) 2(-2.9,2.925) 3(-2.9,2.275) 4(-2.9,1.625) 5(-2.9,0.975) 6(-2.9,0.325) 7(-2.9,-0.325) 8(-2.9,-0.975) 9(-2.9,-1.625) 10(-2.9,-2.275) 11(-2.9,-2.925) 12(-2.9,-3.575) 13(2.9,-3.575) 14(2.9,-2.925) 15(2.9,-2.275) 16(2.9,-1.625) 17(2.9,-0.975) 18(2.9,-0.325) 19(2.9,0.325) 20(2.9,0.975) 21(2.9,1.625) 22(2.9,2.275) 23(2.9,2.925) 24(2.9,3.575)
  silkscreen extent -4.16,-3.95 1.78,3.95
RSV0016A [mm] "QFN, 16-Leads, Body 1.8x2.6mm, Pitch 0.4mm, TI Recommended"
  rect 0.7x0.2 smd: 1(-0.75,0.6)
  rect 0.6x0.2 smd: 2(-0.8,0.2) 3(-0.8,-0.2) 4(-0.8,-0.6) 9(0.8,-0.6) 10(0.8,-0.2) 11(0.8,0.2) 12(0.8,0.6)
  rect 0.2x0.6 smd: 5(-0.6,-1.2) 6(-0.2,-1.2) 7(0.2,-1.2) 8(0.6,-1.2) 13(0.6,1.2) 14(0.2,1.2) 15(-0.2,1.2) 16(-0.6,1.2)
  silkscreen extent -1.08,-1.33 1.08,1.45
Samtec_QSH-030-01-X-D-A [mm] "Receptacle, 0.5 mm, 30x2, TH"
  rect 2.27x0.279 smd: 1(-2.865,7.25) 2(2.865,7.25) 3(-2.865,6.75) 4(2.865,6.75) 5(-2.865,6.25) 6(2.865,6.25) 7(-2.865,5.75) 8(2.865,5.75) 9(-2.865,5.25) 10(2.865,5.25) 11(-2.865,4.75) 12(2.865,4.75) 13(-2.865,4.25) 14(2.865,4.25) 15(-2.865,3.75) 16(2.865,3.75) 17(-2.865,3.25) 18(2.865,3.25) 19(-2.865,2.75) 20(2.865,2.75) 21(-2.865,2.25) 22(2.865,2.25) 23(-2.865,1.75) 24(2.865,1.75) 25(-2.865,1.25) 26(2.865,1.25) 27(-2.865,0.75) 28(2.865,0.75) 29(-2.865,0.25) 30(2.865,0.25) 31(-2.865,-0.25) 32(2.865,-0.25) 33(-2.865,-0.75) 34(2.865,-0.75) 35(-2.865,-1.25) 36(2.865,-1.25) 37(-2.865,-1.75) 38(2.865,-1.75) 39(-2.865,-2.25) 40(2.865,-2.25) 41(-2.865,-2.75) 42(2.865,-2.75) 43(-2.865,-3.25) 44(2.865,-3.25) 45(-2.865,-3.75) 46(2.865,-3.75) 47(-2.865,-4.25) 48(2.865,-4.25) 49(-2.865,-4.75) 50(2.865,-4.75) 51(-2.865,-5.25) 52(2.865,-5.25) 53(-2.865,-5.75) 54(2.865,-5.75) 55(-2.865,-6.25) 56(2.865,-6.25) 57(-2.865,-6.75) 58(2.865,-6.75) 59(-2.865,-7.25) 60(2.865,-7.25)
  round 0 hole 1.02 unplated mask+0: MH1(2.67,10.065) MH2(2.67,-10.065)
  rect 0.43x2.54 smd: MP1(0,8.065) MP4(0,-8.065)
  rect 0.43x4.7 smd: MP2(0,3.175) MP3(0,-3.175)
  silkscreen extent -3.9,-10.66 3.62,10.66
Samtec_SSM-110-x-DV [mm] "Receptacle, 2.54mm, 10x2, SMT"
  rrect10% 1.02x2.22 smd: 1(-11.43,2.825) 2(-11.43,-2.825) 3(-8.89,2.825) 4(-8.89,-2.825) 5(-6.35,2.825) 6(-6.35,-2.825) 7(-3.81,2.825) 8(-3.81,-2.825) 9(-1.27,2.825) 10(-1.27,-2.825) 11(1.27,2.825) 12(1.27,-2.825) 13(3.81,2.825) 14(3.81,-2.825) 15(6.35,2.825) 16(6.35,-2.825) 17(8.89,2.825) 18(8.89,-2.825) 19(11.43,2.825) 20(11.43,-2.825)
  silkscreen extent -13.02,-2.54 12.7,2.54
SMB [mil] "Molded Diode, 2-Leads, Body 5.4x3.6mm, IPC Medium Density, based on OnSemi component dimensions"
  rect 85x107.99 smd: 1(-87.01,0) 2(87.01,0)
  silkscreen extent -155,-82 125,82
SOD-128 [mm] "SMD, 2-Leads, Body 4x2.7mm, Height 1.1mm"
  rect 1.4x2.1 smd paste-0.1: 1(-2.2,0) 2(2.2,0)
  silkscreen extent -3.45,-1.45 2.95,1.45
SOIC-8 [mm] "duplicate of SO-8.  SOIC, 8-Leads, Body 5.0x4.0mm (max), Pitch 1.27mm, IPC Medium Density"
  rrect17% 1.45x0.6 smd: 1(-2.725,1.905) 2(-2.725,0.635) 3(-2.725,-0.635) 4(-2.725,-1.905) 5(2.725,-1.905) 6(2.725,-0.635) 7(2.725,0.635) 8(2.725,1.905)
  silkscreen extent -3.5,-2.5 0.9,2.5
SOT-323 [mm] "Diodes Inc recommended land pattern.  2016-02-24"
  rrect21% 0.6x0.47 smd: 1(-0.95,0.65) 2(-0.95,-0.65) 3(0.95,0)
  silkscreen extent -1.14,-1.22 0.77,1.22
Sullins_xxC07SAAN [mm] "Header, 2.54 mm, 7x1, TH"
  rect 1.55x1.55 hole 1.016: 1(-7.62,0)
  round 1.55 hole 1.016: 2(-5.08,0) 3(-2.54,0) 4(0,0) 5(2.54,0) 6(5.08,0) 7(7.62,0)
  silkscreen extent -8.89,-1.8 8.89,1.27
SW_218-2LP [mm] "SMD, 4-Leads, Body 3.71x5.8mm, Pitch 1.27mm"
  rect 1.27x0.76 smd: 1(-3.81,0.635) 2(-3.81,-0.635) 3(3.81,-0.635) 4(3.81,0.635)
  silkscreen extent -2.9,-1.86 2.9,2.09
SW_218-4LPST [mil] "CTS Components"
  rect 50x30 smd: 1(-150,75) 2(-150,25) 3(-150,-25) 4(-150,-75) 5(150,-75) 6(150,-25) 7(150,25) 8(150,75)
  silkscreen extent -114,-123 114,123
SW_218-6LPST [mm] "SMD, 12-Leads, Body 5.8x8.79mm"
  rect 1.27x0.76 smd: 1(-3.81,3.175) 2(-3.81,1.905) 3(-3.81,0.635) 4(-3.81,-0.635) 5(-3.81,-1.905) 6(-3.81,-3.175) 7(3.81,-3.175) 7(3.81,-3.175) 8(3.81,-1.905) 9(3.81,-0.635) 10(3.81,0.635) 11(3.81,1.905) 12(3.81,3.175)
  silkscreen extent -2.9,-4.4 2.9,4.7
SW_KMR243GLFG [mm] "SMD, 5-Leads, Body 4.2x2.8mm"
  rrect11% 0.9x1 smd: 1(-2.05,0.8) 2(2.05,0.8) 3(-2.05,-0.8) 4(2.05,-0.8)
  rrect18% 1.7x0.55 smd: 5(0,1.425)
  silkscreen extent -3.1,0.7 -2.9,0.9
TI_Stacked_Overlay_Small [mil]
TLMx1000_Yellow [mm] "SMD, 2-Leads, Body 1.6x0.8mm"
  rrect17% 0.6x0.8 smd: 1(-0.725,0) 2(0.725,0)
  silkscreen extent -0.98,-0.8 1.6,0.8
TP_25MIL-SMT [mil]
  round 25 smd paste+0 mask-2.5: 1(0,0)
TP_VIA_060RND040 [mil] "TP_VIA_060RND040"
  round 60 hole 40: 1(0,0)
WEEE_Minimum [mil] "WEEElie bin"
  silkscreen extent 22,-71 54,74
Wurth_61300311021 [mm] "Header, 2.54 mm, 3x1, R/A, TH"
  rect 1.6x1.6 hole 1.1: 1(-2.54,0)
  round 1.6 hole 1.1: 2(0,0) 3(2.54,0)
  silkscreen extent -4.25,-4.04 3.81,-1.5

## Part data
C1 C64 C103: library part CMP-0008770-2, "CAP, CERM, 22 uF, 6.3 V, +/- 10%, X7R, AEC-Q200 Grade 1, 1206"
C2 C37 C38 C40 C41 C43 C94 C95 C99 C106 C113 C116 C125 C126: library part CMP-0078241-1, "CAP, CERM, 0.1 µF, 10 V,+/- 10%, X7R, 0402"
C3 C18 C22 C78: library part CMP-0088425-1, "1µF ±10% 6.3V Ceramic Capacitor X7R 0402 (1005 Metric)"
C4 C5 C7 C8 C10 C11 C12 C14 C16 C19 C21 C25 C26 C28 C29 C85 C101: library part CMP-0078265-1, "CAP, CERM, 0.22 µF, 16 V,+/- 10%, X7R, AEC-Q200 Grade 1, 0402"
C6: library part CMP-0006330-2, "CAP, CERM, 0.047 uF, 50 V, +/- 10%, X7R, AEC-Q200 Grade 1, 0402"
C9 C17 C20: library part CMP-0094968-1, "Multi-Layer Ceramic Capacitor 2.2uF 10V X7S ±10% 0402 Paper T/R"
C13 C15 C23 C44: library part CMP-0086534-1, "Chip Multilayer Ceramic Capacitors for Automotive"
C24 C27: library part CMP-0094778-1, "Multilayer Ceramic Capacitors MLCC - SMD/SMT 0805 4.7uF 10%, 16VDC,  X7R 15%"
C30 C45 C88 C90 C102 C115 C118: library part CMP-0006352-2, "CAP, CERM, 0.01 uF, 25 V, +/- 10%, X7R, 0402"
C31: library part CMP-0064969-1, "CAP, CERM, 0.1 uF, 10 V,+/- 10%, X7S, 0201"
C32 C33: library part CMP-0006367-2, "CAP, CERM, 4.7 pF, 50 V, +/- 2%, C0G/NP0, 0402"
C34 C36 C53 C57 C58 C59 C65 C75 C89 C91 C123 C133 C134: library part CMP-0006356-2, "CAP, CERM, 0.1 uF, 50 V, +/- 10%, X7R, AEC-Q200 Grade 1, 0402"
C35: library part CMP-0007136-5, "CAP, CERM, 1 uF, 16 V, +/- 10%, X7R, AEC-Q200 Grade 1, 0603"
C39: library part CMP-0006361-2, "CAP, CERM, 4700 pF, 50 V, +/- 10%, X7R, AEC-Q200 Grade 1, 0402"
C42 C105 C124: library part CMP-0006302-2, "CAP, CERM, 2.2 uF, 10 V, +/- 10%, X7S, 0402"
C46 C47: library part CMP-0006339-4, "CAP, CERM, 10 uF, 10 V, +/- 20%, X5R, 0402"
C48 C63: library part CMP-0078216-1, "CAP, TA, 47 µF, 10 V, +/- 10%, SMD"
C49 C50 C52: library part CMP-0086440-1, "Cap Ceramic 0.1uF 35V X5R 10% Pad SMD 0201 85C T/R"
C51 C93 C108 C114 C127 C136 C137: library part CMP-0006272-2, "CAP, CERM, 1 uF, 10 V, +/- 10%, X6S, 0402"
C54 C61 C79 C87 C107 C121 C122 C130 C131: library part CMP-0092150-1, "Chip Multilayer Ceramic Capacitors for General Purpose, 1206, 22uF, X7R, 15%, 20%, 6.3V"
C55: library part CMP-0008944-2, "CAP, CERM, 47 uF, 10 V, +/- 10%, X5R, 1206"
C56 C62 C70 C71 C72 C119 C120 C128 C129 C135: library part CMP-0007497-5, "CAP, CERM, 10 uF, 10 V, +/- 20%, X7R, 0603"
C60 C66 C73: library part CMP-0007398-4, "CAP, CERM, 0.47 uF, 16 V, +/- 10%, X7R, 0603"
C67 C69 C74: library part CMP-0006470-2, "CAP, CERM, 470 pF, 50 V, +/- 5%, C0G/NP0, 0402"
C68: library part CMP-0008940-2, "CAP, CERM, 47 uF, 6.3 V, +/- 20%, X5R, 1206"
C76 C77 C84 C92: library part CMP-0064967-2, "CAP, CERM, 0.47 uF, 10 V,+/- 10%, X7S, 0402"
C80 C81 C82 C83 C104 C111: library part CMP-0091983-1, "22µF ±20% 6.3V Ceramic Capacitor X7T 0805 (2012 Metric)"
C86 C96: library part CMP-0007497-5, "CAP, CERM, 10 uF, 10 V, +/- 10%, X5R, 0603"
C97 C98: library part CMP-0860185-1, "CAP, CERM, 8 pF, 50 V,+/- 6.25%, C0G/NP0, 0402"
C100: library part CMP-0006307-2, "CAP, CERM, 10 pF, 50 V, +/- 5%, C0G/NP0, AEC-Q200 Grade 1, 0402"
C109 C110 C112: library part CMP-0008017-2, "CAP, CERM, 10 uF, 10 V, +/- 10%, X7R, 0805"
C117: library part CMP-0078217-1, "CAP, CERM, 15 pF, 50 V,+/- 1%, C0G/NP0, 0402"
C132: library part CMP-0006218-2, "CAP, CERM, 220 pF, 50 V, +/- 5%, C0G/NP0, 0402"
"CAUTION HOT SURFACE1": library part CMP-0074837-2, "IEC 61010-1 Hot Surface Warning"
D1 D2 D8: library part CMP-0078758-2, "Diode, Schottky, 30 V, 2 A, AEC-Q101, SOD-128"
D3: library part CMP-0078196-2, "LED, Yellow, SMD"
D4: library part CMP-0078243-3, "Diode, TVS, Uni, 5.8 V, 10.5 Vc, AEC-Q101, SMB"
D5 D6 D7: library part CMP-0067682-2, "LED, Green, SMD"
D9: library part CMP-0067681-2, "LED, Red, SMD"
F1: library part CMP-0003458-2, "Fuse, 5 A, 32VAC/VDC, SMD"
FB1 FB2: library part CMP-0003364-1, "Ferrite Bead, 30 ohm @ 100 MHz, 4 A, 0805"
FID1 FID2 FID3 FID4 FID5 FID6: library part CMP-0077181-1, "Fiducial mark.  There is nothing to buy or mount."
J1: library part CMP-0054795-1, "Header, 2.54 mm, 3x1, Gold, R/A, TH"
J2: library part CMP-0054584-1, "Header, 2.54 mm, 7x1, Gold, TH"
J3: library part CMP-0087785-1, "CONN HEADER R/A 3POS 1.27MM"
J4: library part CMP-0087187-1, "CONN HDR 1.27MM R/A AU 4POS"
J5: library part CMP-0055293-1, "Connector, Receptacle, Micro-USB Type B, R/A, Bottom Mount SMT"
J6: library part CMP-0075524-1, "Receptacle, 0.5 mm, 30x2, Gold, TH"
J7: library part CMP-0078270-1, "DC POWER JACK, R/A, TH"
J8 J9: library part CMP-0078182-1, "Receptacle, 2.54mm, 10x2, Gold with Tin tail, SMT"
L1 L4 L5 L6: library part CMP-0095018-1, "100nH Shielded Multilayer Inductor 4A 19mOhm Max 0806 (2016 Metric)"
L9 L11: library part CMP-0078934-1, "Inductor, Ferrite Bead, Ferrite, 2.2 A, 0.035 ohm, AEC-Q200 Grade 1, SMD"
L13 L14 L15: library part CMP-0092096-1, "470nH Shielded Wirewound Inductor 3A 42mOhm Max 0805 (2012 Metric)"
LBL1: library part CMP-0003625-1, "Thermal Transfer Printable Labels, 0.650\" W x 0.200\" H - 10,000 per roll"
Logo1: library part CMP-0074838-1, "Texas Instrument Corporate Signature"
Logo2: library part CMP-0074844-1
LOGO3: library part CMP-0074847-1, "FCC_disclaimer"
Logo4: library part CMP-0074769-1
Q1 Q2 Q3 Q4: library part CMP-0000948-2, "MOSFET, N-CH, 100 V, 0.17 A, SOT-323"
R1 R9 R30 R31 R32 R87 R129 R130 R132: library part CMP-0025884-3, "RES, 0, 5%, 0.125 W, 0603"
R2 R4 R5 R7 R8 R14 R17 R20 R22 R23 R27 R44 R49 R54 R65 R67 R71 R72 R75 R76 R81 R82 R90 R91 R94 R97 R98 R101 R102 R103 R104 R105 R106 R107 R112 R113 R114 R115 R116 R117 R123 R131 R135 R136 R138 R142 R148 R150 R152 R157 R158 R161 R162 R165 R203 R206 R231: library part CMP-0025958-3, "RES, 10.0 k, 1%, 0.063 W, AEC-Q200 Grade 0, 0402"
R3 R15 R18 R19 R24 R26 R78 R80 R88 R127 R128 R156 R170 R181 R188 R197 R199 R241: library part CMP-0026992-3, "RES, 0, 5%, 0.1 W, AEC-Q200 Grade 0, 0402"
R6 R33: library part CMP-0026938-5, "RES, 4.7 k, 5%, 0.063 W, AEC-Q200 Grade 0, 0402"
R10: library part CMP-0026403-2, "RES, 49.9 k, 1%, 0.063 W, AEC-Q200 Grade 0, 0402"
R11 R73 R74 R95 R96 R99: library part CMP-0025950-3, "RES, 100 k, 1%, 0.063 W, AEC-Q200 Grade 0, 0402"
R12: library part CMP-0078244-2, "RES, 30.0 k, 1%, 0.063 W, AEC-Q200 Grade 0, 0402"
R13 R16: library part CMP-0026542-2, "RES, 750, 1%, 0.063 W, AEC-Q200 Grade 0, 0402"
R21 R70 R86 R89 R191 R194 R195 R196 R233: library part CMP-0026071-3, "RES, 1.00 k, 1%, 0.063 W, AEC-Q200 Grade 0, 0402"
R25 R29 R34 R35 R36 R37 R38 R39 R40 R41 R42 R52 R53 R55 R56 R58 R59 R60 R61 R62 R63 R69 R77 R83 R84 R85 R100 R108 R109 R110 R111 R118 R133 R137 R139 R140 R143 R144 R145 R146 R147 R149 R153 R154 R155 R159 R160 R163 R164 R190 R219 R220 R221 R222 R223 R224 R225 R226 R227 R228 R229 R230: library part CMP-0027008-4, "RES, 0, 5%, 0.05 W, 0201"
R28 R66 R141 R171 R174: library part CMP-0027137-1, "RES, 510, 5%, 0.05 W, 0201"
R43 R178 R180: library part CMP-0026058-3, "RES, 18.0 k, 1%, 0.063 W, AEC-Q200 Grade 0, 0402"
R45 R46 R47 R48 R51 R93 R122 R124 R125 R126: library part CMP-0027275-3, "RES, 33.2, 1%, 0.05 W, 0201"
R50: library part CMP-0095013-1, "Res Thick Film 0402 47.5K Ohm 1% 1/16W ±100ppm/°C Molded SMD Paper T/R"
R57 R151: library part CMP-0026822-3, "RES, 0, 5%, 0.063 W, AEC-Q200 Grade 0, 0402"
R64 R213: library part CMP-0027072-1, "RES, 220, 5%, 0.05 W, 0201"
R68 R79: library part CMP-0026491-2, "RES, 61.9, 1%, 0.063 W, AEC-Q200 Grade 0, 0402"
R92 R182 R183: library part CMP-0091690-1, "RES 0 OHM JUMPER 1/4W 0603"
R119 R121: library part CMP-0095242-1, "68kO ±1% 0.063W 0402 Thick Film Chip Resistor AEC-Q200 compliant"
R120 R201 R215: library part CMP-0027261-3, "RES, 100 k, 1%, 0.05 W, 0201"
R134: library part CMP-0098430-1, "Res Metal Strip 1206 0.02 Ohm 1% 1/4W ±75ppm/°C Molded SMD SMD T/R"
R169: library part CMP-0026993-2, "RES, 100, 5%, 0.1 W, AEC-Q200 Grade 0, 0402"
R172 R179: library part CMP-0078212-1, "RES, 510, 5%, 0.1 W, AEC-Q200 Grade 0, 0402"
R173 R176 R198 R214: library part CMP-0086442-2, "RES SMD 0 OHM JUMPER 1/20W 0201"
R175 R177 R232 R238 R244: library part CMP-0092204-1, "100 kOhms ±1% 0.063W, 1/16W Chip Resistor 0402 (1005 Metric)  Thick Film"
R192 R193 R200: library part CMP-0098431-1, "40 mOhms ±1% 0.25W, 1/4W Chip Resistor Automotive AEC-Q200, Current Sense, Moisture Resistant, Pulse Withstanding Metal Element"
R202: library part CMP-0026404-2, "RES, 49.9, 1%, 0.063 W, AEC-Q200 Grade 0, 0402"
R204 R207: library part CMP-0026557-2, "RES, 7.87 k, 1%, 0.063 W, AEC-Q200 Grade 0, 0402"
R205 R208: library part CMP-0026574-2, "RES, 82.5 k, 1%, 0.063 W, AEC-Q200 Grade 0, 0402"
R234: library part CMP-0026413-2, "RES, 4.87 k, 1%, 0.063 W, AEC-Q200 Grade 0, 0402"
R236 R239: library part CMP-0078210-2, "RES, 330 k, 1%, 0.063 W, AEC-Q200 Grade 0, 0402"
S1: library part CMP-0002304-1, "Switch, SPST, Slide, Off-On, 6 Pos, 0.025A, 24V, SMD"
S2 S3: library part CMP-0002325-1, "Switch, SPST-NO, Off-Mom, 0.01 A, 32 VDC, SMD"
S4: library part CMP-0002128-3, "Switch, Slide, SPST 4 poles, SMT"
S5: library part CMP-0002230-1, "Switch, SPST, 2 Pos, 25mA, 24VDC, SMD"
TP1 TP2 TP3 TP4 TP5 TP6 TP7 TP8 TP9 TP11 TP12: library part CMP-0078143-3, "TEST POINT.  No entry in BOM."
TP10: library part CMP-0055138-2, "Test Point, Miniature, Black, TH"
U1: library part CMP-0095272-2
U2: library part CMP-0093403-2, "NOR Flash 16Mbit 16M x 1/8M x 2/4M x 4 Serial-SPI 3.3V 8-Pin WSON"
U3: library part CMP-0067398-2, "Automotive Grade, 1.4V-Capable +/-0.5degC Temperature Sensor with Alert Function and I2C/SMBus, DRL0006A (SOT-OTHER-6)"
U4 U24: library part CMP-0067415-1, "10-Ohm Quad SPDT Analog Switch, RSV0016A (UQFN-16)"
U5: library part CMP-0075992-1, "Automotive Fault Protected CAN Transceiver With Flexible Data-Rate, D0008A (SOIC-8)"
U6 U7 U8 U25: library part CMP-0098432-1, "Current Sense Amplifier 1 Circuit 10-VSSOP"
U9: library part CMP-0043115-3, "4-Channel ESD Protection Array for High-Speed Data Interfaces, DRY0006A (USON-6)"
U10 U14: library part CMP-0029468-1, "400 Mbps Enhanced Product Quad LVDS Transmitter with LVTTL Input and Output, 4 Tx and 0 Rx, -55 to +125 degC, 16-pin SOIC (D), Green (RoHS & no Sb/Br)"
U11: library part CMP-0005309-2, "IC, EEPROM, 8KBIT, 400KHZ, 8SOIC"
U12: library part CMP-0067412-1, "0.45-Ohm Quad SPDT Analog Switch Quad-Channel 2:1 Multiplexer/Demultiplexer with Two Controls, PW0016A (TSSOP-16)"
U13: library part CMP-0036402-3, "Single Output High PSRR LDO, 1 A, Adjustable 1.2 to 5.5 V Output, 2.7 to 5.5 V Input, 8-pin SON (DRB), -40 to 125 degC, Green (RoHS & no Sb/Br)"
U15: library part CMP-0092155-1, "3.3-V, 2:1 (SPDT), 6-channel analog multiplexer with 1.8-V compatible control inputs 24-TSSOP -40 to 85"
U16: library part CMP-0088593-2, "1.6 V to 5 V, 2.5-A Low IQ Power Mux With Manual and Automatic Switchover"
U17: library part CMP-0051215-4, "Single 3-Input Positive-AND Gate, DSF0006A, LARGE T&R"
U18: library part CMP-0092337-2, "2.7-V to 6-V, 2-A Automotive Step-Down Converter in SOT583 Package"
U19: library part CMP-0088303-1, "2.7-V to 6-V Adjustable-Frequency Step-Down Converter in SOT583 Package"
U20: library part CMP-0088311-1, "2.7-V to 6-V Adjustable-Frequency Step-Down Converter in SOT583 Package"
U21: library part CMP-0029856-2, "Tiva C Series Microcontroller, 1024 KB Flash, 256 KB SRAM, 12 Bit, 20 Channels, -40 to 105 degC, 128-Pin TQFP (PDT), Green (RoHS & no Sb/Br), Tray"
U22: library part CMP-0033001-1, "Precision Micropower Shunt Voltage Reference, 0.5% accuracy, 2.5 V, 15 ppm / degC, 15 mA, -40 to 125 degC, 3-pin SOT-23 (DBZ), Green (RoHS & no Sb/Br)"
U23: library part CMP-0090433-1, "Local Interconnect Network (LIN) Transceiver with Dominant State Timeout"
Y1: library part CMP-0090505-1, "40MHz ±10ppm Crystal 8pF 50 Ohms 4-SMD, No Lead"
Y2: library part CMP-0095014-1, "16 MHz ±15ppm Crystal 8pF 80 Ohms 4-SMD, No Lead"
ZZ1: library part CMP-0003616-3
ZZ2: library part CMP-0077236-1
ZZ3: library part CMP-0077237-1
ZZ4 ZZ5: library part CMP-0077238-1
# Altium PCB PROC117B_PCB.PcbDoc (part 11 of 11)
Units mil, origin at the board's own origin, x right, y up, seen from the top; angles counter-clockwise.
Board outline 2480.32 x 3185.25 mil, 8 copper layers (Top Layer, L2_GND1, L3_SIG1, L4_PWR1, L5_PWR2, L6_SIG2, L7_GND2, Bottom Layer), stack 57.4 mil thick; 456 components, 292 nets, 7831 pads, 2905 vias.

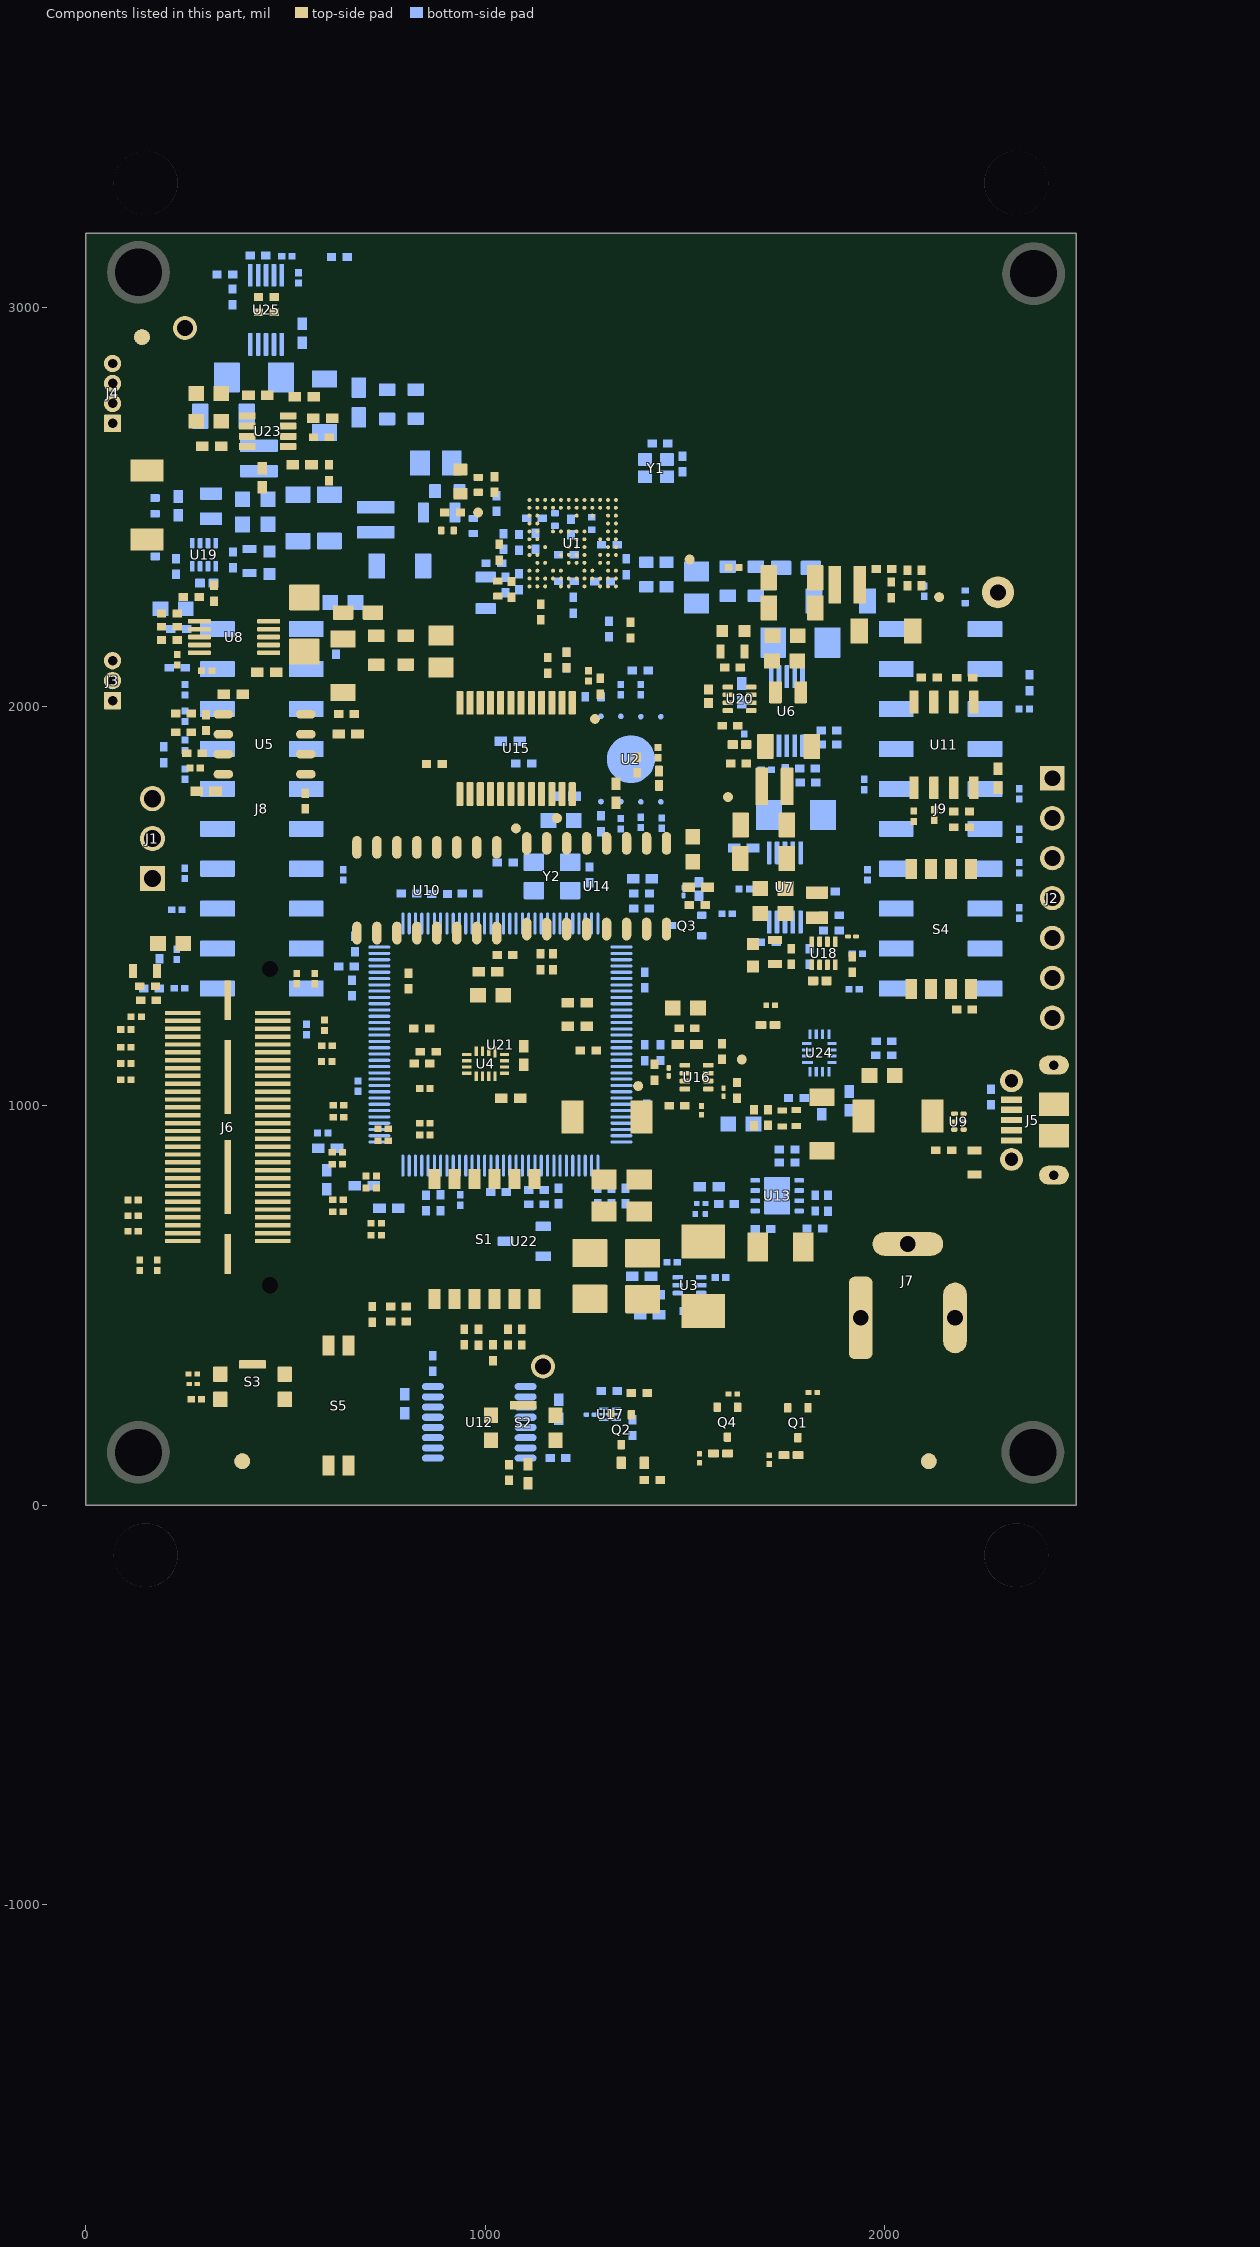
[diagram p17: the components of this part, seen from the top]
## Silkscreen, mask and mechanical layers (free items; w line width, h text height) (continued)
RX:
  lines w0.5: 1062.07,2791.38 1062.07,2841.81 1127.03,2841.81 1127.03,2791.38 1096.52,2791.38 1096.52,2777.64 1092.58,2777.64 1092.58,2791.38 1062.07,2791.38 ; 1062.07,2886.57 1062.07,2937 1127.03,2937 1127.03,2886.57 1100.46,2886.57 1100.46,2899.01 1088.65,2899.01 1088.65,2886.57 1062.07,2886.57 ; 1089.9,2731.78 1089.9,2751.46 1099.2,2751.46 1099.2,2731.78 1089.9,2731.78 ; 1090.18,2751.46 1090.18,2777.64 1098.92,2777.64 1098.92,2751.46 1090.18,2751.46 ; 1092.58,2841.81 1092.58,2937 1096.52,2937 1096.52,2841.81 1092.58,2841.81 ; 1157.26,2886.58 1187.77,2886.58 1187.77,2872.84 1191.7,2872.84 1191.7,2886.58 1222.22,2886.58 1222.22,2937.01 1157.26,2937.01 1157.26,2886.58 ; 1157.26,2981.76 1183.83,2981.76 1183.83,2994.2 1195.64,2994.2 1195.64,2981.76 1222.22,2981.76 1222.22,3032.2 1157.26,3032.2 1157.26,2981.76 ; 1185.09,2826.97 1194.39,2826.97 1194.39,2846.66 1185.09,2846.66 1185.09,2826.97 ; 1185.36,2846.66 1194.11,2846.66 1194.11,2872.84 1185.36,2872.84 1185.36,2846.66 ; 1187.77,2937.01 1191.7,2937.01 1191.7,3032.2 1187.77,3032.2 1187.77,2937.01 ; 1252.44,2791.38 1282.95,2791.38 1282.95,2777.64 1286.89,2777.64 1286.89,2791.38 1317.4,2791.38 1317.4,2841.81 1252.44,2841.81 1252.44,2791.38 ; 1252.44,2886.57 1279.01,2886.57 1279.01,2899.01 1290.83,2899.01 1290.83,2886.57 1317.4,2886.57 1317.4,2937 1252.44,2937 1252.44,2886.57 ; 1280.27,2731.78 1289.57,2731.78 1289.57,2751.46 1280.27,2751.46 1280.27,2731.78 ; 1280.55,2751.46 1289.29,2751.46 1289.29,2777.64 1280.55,2777.64 1280.55,2751.46 ; 1282.95,2841.81 1286.89,2841.81 1286.89,2937 1282.95,2937 1282.95,2841.81
SAMTEC CABLE:
  drawing of 5007 lines, arcs and shapes, not listed
DCA1000:
  drawing of 10999 lines, arcs and shapes, not listed
fanoutbga:
  drawing of 566 lines, arcs and shapes, not listed
PCB_dimesnion_airgap_trace_width:
  lines w0.5: 1112.97,2475.92 1278.32,2475.92 ; 1112.97,2475.92 1112.97,2556.62 ; 1112.97,2475.92 1278.32,2475.92 ; 1112.97,2475.92 1112.97,2517.25 ; 1112.97,2475.92 1278.32,2475.92 ; 1112.97,2475.92 1112.97,2556.62 ; 1112.97,2517.25 1150.36,2517.25 ; 1112.97,2517.25 1150.36,2517.25 ; 1112.97,2517.25 1112.97,2556.62 ; 1112.97,2556.62 1278.32,2556.62 ; 1112.97,2556.62 1278.32,2556.62 ; 1112.97,2556.62 1278.32,2556.62 ; 1112.97,2556.62 1112.97,2476.5 1278.32,2476.5 1278.32,2556.62 ; 1112.97,2556.62 1278.32,2556.62 ; 1150.36,2517.25 ccw(c1150.37,2517.25) 1150.37,2517.25 ; 1150.37,2517.25 ccw(c1150.37,2517.25) 1150.37,2517.25 ; 1150.37,2517.25 ccw(c1150.37,2517.25) 1150.36,2517.25 ; 1150.37,2517.25 1189.73,2517.25 ; 1150.37,2517.25 1189.73,2517.25 ; 1189.73,2517.25 ccw(c1189.74,2517.25) 1189.74,2517.25 ; 1189.74,2517.25 cw(c1189.74,2517.25) 1189.74,2517.25 ; 1189.74,2517.25 ccw(c1189.74,2517.25) 1189.73,2517.25 ; 1189.74,2517.25 1229.1,2517.25 ; 1189.74,2517.25 1229.1,2517.25 ; 1229.1,2517.25 ccw(c1229.11,2517.25) 1229.11,2517.25 ; 1229.11,2517.25 ccw(c1229.11,2517.25) 1229.1,2517.25 ; 1278.32,2475.92 1278.32,2556.62 ; 1278.32,2475.92 1114.96,2475.92 1114.96,2556.62 1140.38,2556.62 1140.38,2536.94 1160.36,2536.94 1160.36,2556.62 1179.75,2556.62 1179.75,2536.94 1199.73,2536.94 1199.73,2556.62 1219.12,2556.62 1219.12,2536.94 1239.1,2536.94 1239.1,2556.62 1278.32,2556.62 ; 1278.32,2475.92 1278.32,2556.62 ; 1278.32,2475.92 1278.32,2556.62 ; 1278.32,2475.92 1278.32,2556.62 ; 1286.2,2349.93 1286.2,2515.28 ; 1286.2,2349.93 1366.9,2349.93 ; 1286.2,2349.93 1366.9,2349.93 ; 1286.2,2349.93 1286.2,2515.28 ; 1286.2,2349.93 1286.2,2515.28 ; 1286.2,2349.93 1366.9,2349.93 ; 1286.2,2349.93 1286.2,2513.29 1366.9,2513.29 1366.9,2487.87 1347.21,2487.87 1347.21,2467.9 1366.9,2467.9 1366.9,2448.5 1347.21,2448.5 1347.21,2428.53 1366.9,2428.53 1366.9,2409.13 1347.21,2409.13 1347.21,2389.16 1366.9,2389.16 1366.9,2349.93 ; 1286.2,2349.93 1366.9,2349.93 ; 1286.2,2515.28 1366.9,2515.28 ; 1286.2,2515.28 1327.53,2515.28 ; 1286.2,2515.28 1366.9,2515.28 ; 1327.53,2399.14 ccw(c1327.53,2399.14) 1327.53,2399.15 ; 1327.53,2399.15 ccw(c1327.53,2399.14) 1327.53,2399.14 ; 1327.53,2399.15 1327.53,2438.51 ; 1327.53,2399.15 1327.53,2438.51 ; 1327.53,2438.51 ccw(c1327.53,2438.51) 1327.53,2438.52 ; 1327.53,2438.51 ccw(c1327.53,2438.51) 1327.53,2438.51 ; 1327.53,2438.52 ccw(c1327.53,2438.51) 1327.53,2438.51 ; 1327.53,2438.52 1327.53,2477.88 ; 1327.53,2438.52 1327.53,2477.88 ; 1327.53,2477.88 ccw(c1327.53,2477.88) 1327.53,2477.89 ; 1327.53,2477.88 ccw(c1327.53,2477.88) 1327.53,2477.88 ; 1327.53,2477.88 cw(c1327.53,2477.88) 1327.53,2477.89 ; 1327.53,2477.89 1327.53,2515.28 ; 1327.53,2477.89 1327.53,2515.28 ; 1327.53,2515.28 1366.9,2515.28 ; 1366.9,2349.93 1366.9,2515.28 ; 1366.9,2349.93 1285.8,2349.93 1285.8,2515.28 1366.9,2515.28 ; 1366.9,2349.93 1366.9,2515.28 ; 1366.9,2349.93 1366.9,2515.28 ; 1366.9,2349.93 1366.9,2515.28 ; 1096.43,2467.42 1294.86,2467.42 1294.86,2564.73 1096.43,2564.73 1096.43,2467.42 ; 1145.72,2518.87 ccw(c1150.36,2517.25) 1155.02,2518.85 1155.02,2556.62 1145.72,2556.62 1145.72,2518.87 ; 1185.09,2518.87 ccw(c1189.73,2517.25) 1194.39,2518.85 1194.39,2556.62 1185.09,2556.62 1185.09,2518.87 ; 1224.46,2518.87 ccw(c1229.1,2517.25) 1233.76,2518.85 1233.76,2556.62 1224.46,2556.62 1224.46,2518.87 ; 1277.69,2333.39 1277.69,2531.82 1375.01,2531.82 1375.01,2333.39 1277.69,2333.39 ; 1329.13,2394.49 cw(c1327.53,2399.15) 1329.15,2403.79 1366.9,2403.79 1366.9,2394.49 1329.13,2394.49 ; 1329.13,2433.87 cw(c1327.53,2438.52) 1329.15,2443.16 1366.9,2443.16 1366.9,2433.86 1329.13,2433.87 ; 1329.13,2473.24 cw(c1327.53,2477.89) 1329.15,2482.53 1366.9,2482.53 1366.9,2473.24 1329.13,2473.24
PROC074B-PCB_dxf:
  drawing of 10310 lines, arcs and shapes, not listed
